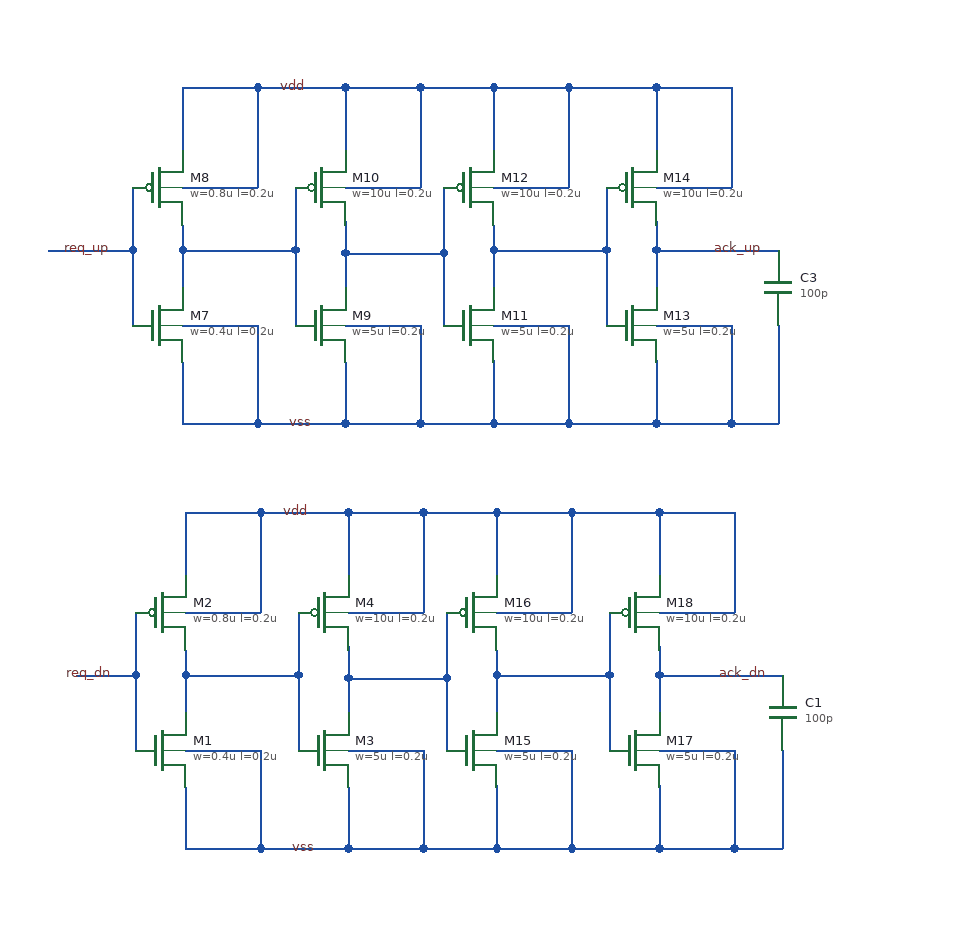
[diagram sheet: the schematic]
v {xschem version=3.4.8RC file_version=1.3}
G {}
K {}
V {}
S {}
F {}
E {}
N 98.75 28.75 136.25 28.75 {lab=vss}
N 136.25 -50 136.25 28.75 {lab=vss}
N -337.5 230 -337.5 260 {lab=#net1}
N -377.5 230 -377.5 290 {lab=req_dn}
N -337.5 100 -337.5 150 {lab=vdd}
N -337.5 290 -277.5 290 {lab=vss}
N -337.5 180 -277.5 180 {lab=vdd}
N -277.5 100 -277.5 180 {lab=vdd}
N -337.5 100 -277.5 100 {lab=vdd}
N -337.5 230 -247.5 230 {lab=#net1}
N -337.5 210 -337.5 230 {lab=#net1}
N -247.5 230 -247.5 290 {lab=#net1}
N -247.5 180 -247.5 230 {lab=#net1}
N -207.5 100 -207.5 150 {lab=vdd}
N -207.5 290 -147.5 290 {lab=vss}
N -207.5 180 -147.5 180 {lab=vdd}
N -147.5 100 -147.5 180 {lab=vdd}
N -207.5 100 -147.5 100 {lab=vdd}
N -277.5 100 -207.5 100 {lab=vdd}
N -425 230 -377.5 230 {lab=req_dn}
N -377.5 180 -377.5 230 {lab=req_dn}
N -147.5 290 -147.5 368.75 {lab=vss}
N -337.5 320 -337.5 368.75 {lab=vss}
N -277.5 290 -277.5 368.75 {lab=vss}
N -207.5 320 -207.5 368.75 {lab=vss}
N 101.25 368.75 140 368.75 {lab=vss}
N -337.5 368.75 -277.5 368.75 {lab=vss}
N -277.5 368.75 -207.5 368.75 {lab=vss}
N -207.5 368.75 -147.5 368.75 {lab=vss}
N 140 290 140 368.75 {lab=vss}
N -207.5 232.5 -207.5 262.578125 {lab=#net2}
N 38.75 -110 136.25 -110 {lab=ack_up}
N -88.75 230 -88.75 260 {lab=#net3}
N -88.75 100 -88.75 150 {lab=vdd}
N -88.75 290 -28.75 290 {lab=vss}
N -88.75 180 -28.75 180 {lab=vdd}
N -28.75 100 -28.75 180 {lab=vdd}
N -88.75 230 1.25 230 {lab=#net3}
N -88.75 210 -88.75 230 {lab=#net3}
N 1.25 230 1.25 290 {lab=#net3}
N 1.25 180 1.25 230 {lab=#net3}
N 41.25 100 41.25 150 {lab=vdd}
N 41.25 290 101.25 290 {lab=vss}
N 41.25 180 101.25 180 {lab=vdd}
N 101.25 100 101.25 180 {lab=vdd}
N 41.25 100 101.25 100 {lab=vdd}
N -28.75 100 41.25 100 {lab=vdd}
N -88.75 100 -28.75 100 {lab=vdd}
N -88.75 318.75 -88.75 368.75 {lab=vss}
N 41.25 318.75 41.25 368.75 {lab=vss}
N -28.75 368.75 41.25 368.75 {lab=vss}
N -128.75 232.5 -128.75 290 {lab=#net2}
N -28.75 290 -28.75 368.75 {lab=vss}
N -88.75 368.75 -28.75 368.75 {lab=vss}
N 101.25 290 101.25 368.75 {lab=vss}
N 41.25 368.75 101.25 368.75 {lab=vss}
N 41.25 230 41.25 262.734375 {lab=ack_dn}
N -147.5 368.75 -88.75 368.75 {lab=vss}
N -147.5 100 -88.75 100 {lab=vdd}
N -207.5 232.5 -128.75 232.5 {lab=#net2}
N -207.5 207.421875 -207.5 232.5 {lab=#net2}
N -128.75 180 -128.75 232.5 {lab=#net2}
N 41.25 230 140 230 {lab=ack_dn}
N 41.25 207.421875 41.25 230 {lab=ack_dn}
N -340 -110 -340 -80 {lab=#net4}
N -340 -240 -340 -190 {lab=vdd}
N -340 -50 -280 -50 {lab=vss}
N -340 -160 -280 -160 {lab=vdd}
N -280 -240 -280 -160 {lab=vdd}
N -340 -240 -280 -240 {lab=vdd}
N -340 -110 -250 -110 {lab=#net4}
N -340 -130 -340 -110 {lab=#net4}
N -250 -110 -250 -50 {lab=#net4}
N -250 -160 -250 -110 {lab=#net4}
N -210 -240 -210 -190 {lab=vdd}
N -210 -50 -150 -50 {lab=vss}
N -210 -160 -150 -160 {lab=vdd}
N -150 -240 -150 -160 {lab=vdd}
N -210 -240 -150 -240 {lab=vdd}
N -280 -240 -210 -240 {lab=vdd}
N -380 -110 -380 -50 {lab=req_up}
N -150 -50 -150 28.75 {lab=vss}
N -340 -20 -340 28.75 {lab=vss}
N -280 -50 -280 28.75 {lab=vss}
N -210 -20 -210 28.75 {lab=vss}
N -340 28.75 -280 28.75 {lab=vss}
N -280 28.75 -210 28.75 {lab=vss}
N -210 28.75 -150 28.75 {lab=vss}
N -210 -107.5 -210 -77.421875 {lab=#net5}
N -91.25 -110 -91.25 -80 {lab=#net6}
N -91.25 -240 -91.25 -190 {lab=vdd}
N -91.25 -50 -31.25 -50 {lab=vss}
N -91.25 -160 -31.25 -160 {lab=vdd}
N -31.25 -240 -31.25 -160 {lab=vdd}
N -91.25 -110 -1.25 -110 {lab=#net6}
N -91.25 -130 -91.25 -110 {lab=#net6}
N -1.25 -110 -1.25 -50 {lab=#net6}
N -1.25 -160 -1.25 -110 {lab=#net6}
N 38.75 -240 38.75 -190 {lab=vdd}
N 38.75 -50 98.75 -50 {lab=vss}
N 38.75 -160 98.75 -160 {lab=vdd}
N 98.75 -240 98.75 -160 {lab=vdd}
N 38.75 -240 98.75 -240 {lab=vdd}
N -31.25 -240 38.75 -240 {lab=vdd}
N -91.25 -240 -31.25 -240 {lab=vdd}
N -91.25 -21.25 -91.25 28.75 {lab=vss}
N 38.75 -21.25 38.75 28.75 {lab=vss}
N -31.25 28.75 38.75 28.75 {lab=vss}
N -131.25 -107.5 -131.25 -50 {lab=#net5}
N -31.25 -50 -31.25 28.75 {lab=vss}
N -91.25 28.75 -31.25 28.75 {lab=vss}
N 98.75 -50 98.75 28.75 {lab=vss}
N 38.75 28.75 98.75 28.75 {lab=vss}
N -150 28.75 -91.25 28.75 {lab=vss}
N -150 -240 -91.25 -240 {lab=vdd}
N -210 -107.5 -131.25 -107.5 {lab=#net5}
N -210 -132.578125 -210 -107.5 {lab=#net5}
N -131.25 -160 -131.25 -107.5 {lab=#net5}
N 38.75 -110 38.75 -77.265625 {lab=ack_up}
N 38.75 -132.578125 38.75 -110 {lab=ack_up}
N -447.5 -110 -380 -110 {lab=req_up}
N -380 -160 -380 -110 {lab=req_up}
N 140 230 140 233.75 {lab=ack_dn}
N 136.25 -110 136.25 -106.875 {lab=ack_up}
C {devices/lab_wire.sym} -396.25 -110 0 0 {name=p32 sig_type=std_logic lab=req_up}
C {capa.sym} 136.25 -80 0 0 {name=C3
m=1
value=100p
footprint=1206
device="ceramic capacitor"}
C {sg13g2_pr/sg13_lv_nmos.sym} -357.5 290 0 0 {name=M1
l=0.2u
w=0.4u
ng=1
m=1
model=sg13_lv_nmos
spiceprefix=X
}
C {sg13g2_pr/sg13_lv_pmos.sym} -357.5 180 0 0 {name=M2
l=0.2u
w=0.8u
ng=1
m=1
model=sg13_lv_pmos
spiceprefix=X
}
C {sg13g2_pr/sg13_lv_nmos.sym} -227.5 290 0 0 {name=M3
l=0.2u
w=5u
ng=1
m=1
model=sg13_lv_nmos
spiceprefix=X
}
C {sg13g2_pr/sg13_lv_pmos.sym} -227.5 180 0 0 {name=M4
l=0.2u
w=10u
ng=1
m=1
model=sg13_lv_pmos
spiceprefix=X
}
C {devices/lab_wire.sym} -395 230 0 0 {name=p29 sig_type=std_logic lab=req_dn}
C {capa.sym} 140 260 0 0 {name=C1
m=1
value=100p
footprint=1206
device="ceramic capacitor"}
C {lab_wire.sym} -262.5 100 2 0 {name=p27 sig_type=std_logic lab=vdd}
C {lab_wire.sym} -255 368.75 2 0 {name=p31 sig_type=std_logic lab=vss}
C {sg13g2_pr/sg13_lv_nmos.sym} -108.75 290 0 0 {name=M15
l=0.2u
w=5u
ng=1
m=1
model=sg13_lv_nmos
spiceprefix=X
}
C {sg13g2_pr/sg13_lv_pmos.sym} -108.75 180 0 0 {name=M16
l=0.2u
w=10u
ng=1
m=1
model=sg13_lv_pmos
spiceprefix=X
}
C {sg13g2_pr/sg13_lv_nmos.sym} 21.25 290 0 0 {name=M17
l=0.2u
w=5u
ng=1
m=1
model=sg13_lv_nmos
spiceprefix=X
}
C {sg13g2_pr/sg13_lv_pmos.sym} 21.25 180 0 0 {name=M18
l=0.2u
w=10u
ng=1
m=1
model=sg13_lv_pmos
spiceprefix=X
}
C {lab_wire.sym} 128.75 230 0 0 {name=p37 sig_type=std_logic lab=ack_dn}
C {lab_wire.sym} 125 -110 0 0 {name=p47 sig_type=std_logic lab=ack_up}
C {sg13g2_pr/sg13_lv_nmos.sym} -360 -50 0 0 {name=M7
l=0.2u
w=0.4u
ng=1
m=1
model=sg13_lv_nmos
spiceprefix=X
}
C {sg13g2_pr/sg13_lv_pmos.sym} -360 -160 0 0 {name=M8
l=0.2u
w=0.8u
ng=1
m=1
model=sg13_lv_pmos
spiceprefix=X
}
C {sg13g2_pr/sg13_lv_nmos.sym} -230 -50 0 0 {name=M9
l=0.2u
w=5u
ng=1
m=1
model=sg13_lv_nmos
spiceprefix=X
}
C {sg13g2_pr/sg13_lv_pmos.sym} -230 -160 0 0 {name=M10
l=0.2u
w=10u
ng=1
m=1
model=sg13_lv_pmos
spiceprefix=X
}
C {lab_wire.sym} -265 -240 2 0 {name=p23 sig_type=std_logic lab=vdd}
C {lab_wire.sym} -257.5 28.75 2 0 {name=p24 sig_type=std_logic lab=vss}
C {sg13g2_pr/sg13_lv_nmos.sym} -111.25 -50 0 0 {name=M11
l=0.2u
w=5u
ng=1
m=1
model=sg13_lv_nmos
spiceprefix=X
}
C {sg13g2_pr/sg13_lv_pmos.sym} -111.25 -160 0 0 {name=M12
l=0.2u
w=10u
ng=1
m=1
model=sg13_lv_pmos
spiceprefix=X
}
C {sg13g2_pr/sg13_lv_nmos.sym} 18.75 -50 0 0 {name=M13
l=0.2u
w=5u
ng=1
m=1
model=sg13_lv_nmos
spiceprefix=X
}
C {sg13g2_pr/sg13_lv_pmos.sym} 18.75 -160 0 0 {name=M14
l=0.2u
w=10u
ng=1
m=1
model=sg13_lv_pmos
spiceprefix=X
}
